VERSION 5.7 ;
  NOWIREEXTENSIONATPIN ON ;
  DIVIDERCHAR "/" ;
  BUSBITCHARS "[]" ;
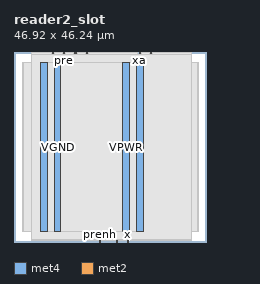
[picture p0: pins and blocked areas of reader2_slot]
MACRO reader2_slot
  CLASS BLOCK ;
  FOREIGN reader2_slot ;
  ORIGIN 0.000 0.000 ;
  SIZE 46.920 BY 46.240 ;
  PIN VGND
    DIRECTION INOUT ;
    USE GROUND ;
    PORT
      LAYER met4 ;
        RECT 9.800 2.480 11.400 43.760 ;
    END
    PORT
      LAYER met4 ;
        RECT 29.800 2.480 31.400 43.760 ;
    END
  END VGND
  PIN VPWR
    DIRECTION INOUT ;
    USE POWER ;
    PORT
      LAYER met4 ;
        RECT 6.500 2.480 8.100 43.760 ;
    END
    PORT
      LAYER met4 ;
        RECT 26.500 2.480 28.100 43.760 ;
    END
  END VPWR
  PIN en
    DIRECTION INPUT ;
    USE SIGNAL ;
    ANTENNAGATEAREA 0.247500 ;
    PORT
      LAYER met2 ;
        RECT 9.290 45.960 9.570 46.240 ;
    END
  END en
  PIN pre
    DIRECTION INPUT ;
    USE SIGNAL ;
    ANTENNAGATEAREA 0.495000 ;
    PORT
      LAYER met2 ;
        RECT 12.050 45.960 12.330 46.240 ;
    END
  END pre
  PIN prenh
    DIRECTION OUTPUT ;
    USE SIGNAL ;
    ANTENNADIFFAREA 1.971000 ;
    PORT
      LAYER met2 ;
        RECT 20.790 0.000 21.070 0.280 ;
    END
  END prenh
  PIN prenl
    DIRECTION OUTPUT ;
    USE SIGNAL ;
    ANTENNADIFFAREA 1.288000 ;
    PORT
      LAYER met2 ;
        RECT 24.930 0.000 25.210 0.280 ;
    END
  END prenl
  PIN src[0]
    DIRECTION INPUT ;
    USE SIGNAL ;
    ANTENNAGATEAREA 1.615500 ;
    PORT
      LAYER met2 ;
        RECT 14.810 45.960 15.090 46.240 ;
    END
  END src[0]
  PIN src[1]
    DIRECTION INPUT ;
    USE SIGNAL ;
    ANTENNAGATEAREA 1.984500 ;
    PORT
      LAYER met2 ;
        RECT 17.570 45.960 17.850 46.240 ;
    END
  END src[1]
  PIN x
    DIRECTION INPUT ;
    USE SIGNAL ;
    ANTENNAGATEAREA 0.247500 ;
    PORT
      LAYER met2 ;
        RECT 27.690 0.000 27.970 0.280 ;
    END
  END x
  PIN xa
    DIRECTION OUTPUT ;
    USE SIGNAL ;
    ANTENNADIFFAREA 0.445500 ;
    PORT
      LAYER met2 ;
        RECT 30.450 45.960 30.730 46.240 ;
    END
  END xa
  PIN xb
    DIRECTION OUTPUT ;
    USE SIGNAL ;
    ANTENNADIFFAREA 0.445500 ;
    PORT
      LAYER met2 ;
        RECT 33.210 45.960 33.490 46.240 ;
    END
  END xb
  OBS
      LAYER nwell ;
        RECT 2.110 2.635 44.810 43.710 ;
      LAYER li1 ;
        RECT 2.300 2.635 44.620 43.605 ;
      LAYER met1 ;
        RECT 2.300 2.480 44.620 43.760 ;
      LAYER met2 ;
        RECT 4.240 45.680 9.010 46.170 ;
        RECT 9.850 45.680 11.770 46.170 ;
        RECT 12.610 45.680 14.530 46.170 ;
        RECT 15.370 45.680 17.290 46.170 ;
        RECT 18.130 45.680 30.170 46.170 ;
        RECT 31.010 45.680 32.930 46.170 ;
        RECT 33.770 45.680 43.140 46.170 ;
        RECT 4.240 0.560 43.140 45.680 ;
        RECT 4.240 0.280 20.510 0.560 ;
        RECT 21.350 0.280 24.650 0.560 ;
        RECT 25.490 0.280 27.410 0.560 ;
        RECT 28.250 0.280 43.140 0.560 ;
      LAYER met3 ;
        RECT 6.510 2.555 31.390 43.685 ;
  END
END reader2_slot
END LIBRARY

